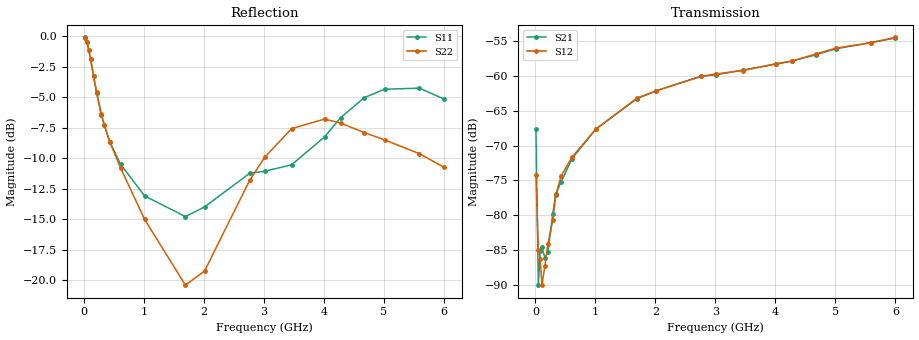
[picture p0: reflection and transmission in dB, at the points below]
!Agilent Technologies,N5230A,MY45001650,A.07.50.48
!Agilent N5230A: A.07.50.48
!Date: Saturday, July 08, 2017 15:47:14
!Correction: S11(Full 2 Port(1,2))
!S21(Full 2 Port(1,2))
!S12(Full 2 Port(1,2))
!S22(Full 2 Port(1,2))
!S2P File: Measurements: S11, S21, S12, S22:
# Hz S  dB  R 50
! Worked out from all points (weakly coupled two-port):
!   600 points, 10 MHz to 6 GHz, reference 50 ohm
!   highest |S21| = -54.57 dB at 6 GHz (marker M1); lowest = -90.0 dB at 50 MHz (marker M2)
!   lowest |S11| = -14.8 dB at 1.69 GHz (marker M3), VSWR 1.45, Z = 34.6 + j1.2 ohm
!   |S11| at or under -10 dB: 553.2 MHz to 3.665 GHz (3.112 GHz wide, 148 % of centre)
!   |S22| runs from -20.6 to -0.1 dB; largest |S21 - S12| = 0.00061
!   S11 on the Smith chart (normalised r, x): 10 MHz: 3, -20; 110 MHz: 0.52, -1.89; 340 MHz: 0.55, -0.54; 2.76 GHz: 0.58, +0.10; 4.28 GHz: 1.40, +1.17; 6 GHz: 2.56, -1.43
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1e7  -0.11 -5.7  -67.62 -47.3  -74.22 144.0  -0.12 -5.7
5e7  -0.50 -26.6  -90.02 -126.0  -84.92 -65.1  -0.50 -26.5
8e7  -1.13 -40.8  -85.18 -167.9  -86.32 -55.4  -1.12 -40.5
1.1e8  -1.91 -53.1  -84.57 152.0  -89.98 -16.2  -1.90 -52.8
1.6e8  -3.31 -70.0  -86.16 90.5  -87.24 93.0  -3.30 -69.6
2.1e8  -4.63 -83.7  -85.24 124.5  -84.12 113.9  -4.59 -83.3
2.9e8  -6.50 -101.5  -79.82 99.0  -80.73 102.1  -6.40 -100.4
3.4e8  -7.32 -110.6  -76.97 92.9  -77.12 89.2  -7.29 -108.9
4.3e8  -8.67 -125.0  -75.21 76.9  -74.38 79.2  -8.67 -122.1
6.1e8  -10.51 -145.6  -71.90 55.2  -71.68 57.9  -10.81 -140.6
1.01e9  -13.10 -172.4  -67.62 14.1  -67.63 13.8  -15.02 -165.4
1.69e9  -14.79 174.7  -63.31 -46.8  -63.22 -47.4  -20.41 -177.6
2.01e9  -14.00 177.0  -62.16 -78.3  -62.16 -77.6  -19.25 -174.7
2.76e9  -11.25 162.3  -60.07 -149.1  -60.09 -148.8  -11.83 162.2
3.01e9  -11.08 149.5  -59.84 -172.6  -59.74 -172.7  -9.94 152.6
3.46e9  -10.55 117.0  -59.18 145.4  -59.24 145.9  -7.59 138.2
4.01e9  -8.26 64.1  -58.33 98.2  -58.27 98.0  -6.80 119.1
4.28e9  -6.68 45.0  -57.87 77.3  -57.87 77.4  -7.14 108.3
4.67e9  -5.05 25.2  -57.00 46.3  -56.88 46.6  -7.91 89.2
5.01e9  -4.36 13.4  -56.13 18.3  -56.03 18.7  -8.51 69.4
5.59e9  -4.27 -4.5  -55.24 -28.9  -55.26 -28.9  -9.64 32.5
6e9  -5.16 -20.6  -54.57 -57.9  -54.49 -58.0  -10.76 9.6
